VERSION 5.7 ;
BUSBITCHARS "[]" ;
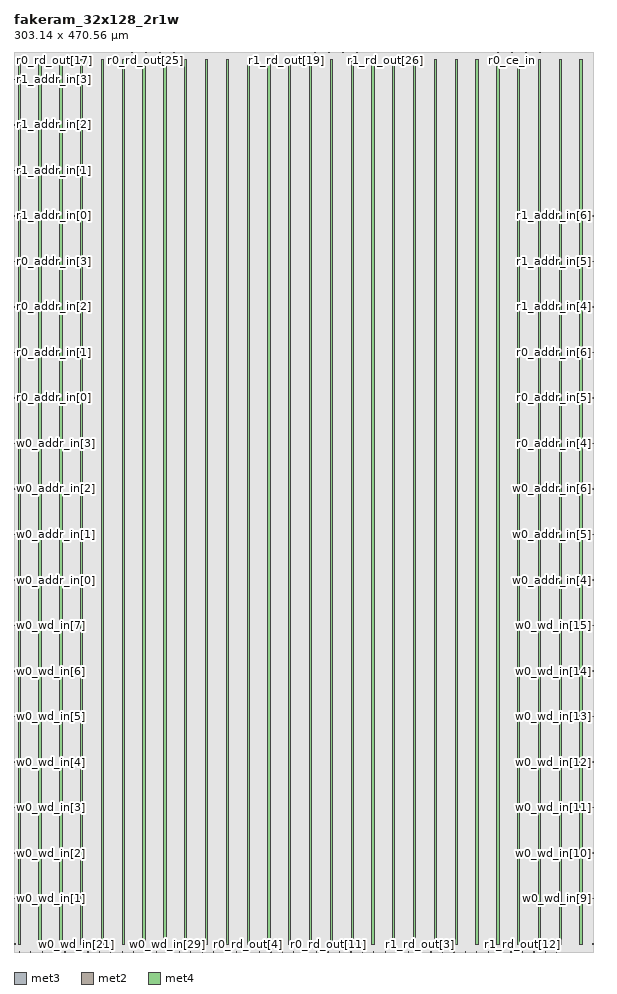
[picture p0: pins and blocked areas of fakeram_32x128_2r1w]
MACRO fakeram_32x128_2r1w
  FOREIGN fakeram_32x128_2r1w 0 0 ;
  SYMMETRY X Y R90 ;
  SIZE 303.140 BY 470.560 ;
  CLASS BLOCK ;
  PIN w0_wd_in[0]
    DIRECTION INPUT ;
    USE SIGNAL ;
    SHAPE ABUTMENT ;
    PORT
      LAYER met3 ;
      RECT 0.000 3.930 0.900 4.230 ;
    END
  END w0_wd_in[0]
  PIN w0_wd_in[1]
    DIRECTION INPUT ;
    USE SIGNAL ;
    SHAPE ABUTMENT ;
    PORT
      LAYER met3 ;
      RECT 0.000 27.730 0.900 28.030 ;
    END
  END w0_wd_in[1]
  PIN w0_wd_in[2]
    DIRECTION INPUT ;
    USE SIGNAL ;
    SHAPE ABUTMENT ;
    PORT
      LAYER met3 ;
      RECT 0.000 51.530 0.900 51.830 ;
    END
  END w0_wd_in[2]
  PIN w0_wd_in[3]
    DIRECTION INPUT ;
    USE SIGNAL ;
    SHAPE ABUTMENT ;
    PORT
      LAYER met3 ;
      RECT 0.000 75.330 0.900 75.630 ;
    END
  END w0_wd_in[3]
  PIN w0_wd_in[4]
    DIRECTION INPUT ;
    USE SIGNAL ;
    SHAPE ABUTMENT ;
    PORT
      LAYER met3 ;
      RECT 0.000 99.130 0.900 99.430 ;
    END
  END w0_wd_in[4]
  PIN w0_wd_in[5]
    DIRECTION INPUT ;
    USE SIGNAL ;
    SHAPE ABUTMENT ;
    PORT
      LAYER met3 ;
      RECT 0.000 122.930 0.900 123.230 ;
    END
  END w0_wd_in[5]
  PIN w0_wd_in[6]
    DIRECTION INPUT ;
    USE SIGNAL ;
    SHAPE ABUTMENT ;
    PORT
      LAYER met3 ;
      RECT 0.000 146.730 0.900 147.030 ;
    END
  END w0_wd_in[6]
  PIN w0_wd_in[7]
    DIRECTION INPUT ;
    USE SIGNAL ;
    SHAPE ABUTMENT ;
    PORT
      LAYER met3 ;
      RECT 0.000 170.530 0.900 170.830 ;
    END
  END w0_wd_in[7]
  PIN w0_wd_in[8]
    DIRECTION INPUT ;
    USE SIGNAL ;
    SHAPE ABUTMENT ;
    PORT
      LAYER met3 ;
      RECT 302.240 3.930 303.140 4.230 ;
    END
  END w0_wd_in[8]
  PIN w0_wd_in[9]
    DIRECTION INPUT ;
    USE SIGNAL ;
    SHAPE ABUTMENT ;
    PORT
      LAYER met3 ;
      RECT 302.240 27.730 303.140 28.030 ;
    END
  END w0_wd_in[9]
  PIN w0_wd_in[10]
    DIRECTION INPUT ;
    USE SIGNAL ;
    SHAPE ABUTMENT ;
    PORT
      LAYER met3 ;
      RECT 302.240 51.530 303.140 51.830 ;
    END
  END w0_wd_in[10]
  PIN w0_wd_in[11]
    DIRECTION INPUT ;
    USE SIGNAL ;
    SHAPE ABUTMENT ;
    PORT
      LAYER met3 ;
      RECT 302.240 75.330 303.140 75.630 ;
    END
  END w0_wd_in[11]
  PIN w0_wd_in[12]
    DIRECTION INPUT ;
    USE SIGNAL ;
    SHAPE ABUTMENT ;
    PORT
      LAYER met3 ;
      RECT 302.240 99.130 303.140 99.430 ;
    END
  END w0_wd_in[12]
  PIN w0_wd_in[13]
    DIRECTION INPUT ;
    USE SIGNAL ;
    SHAPE ABUTMENT ;
    PORT
      LAYER met3 ;
      RECT 302.240 122.930 303.140 123.230 ;
    END
  END w0_wd_in[13]
  PIN w0_wd_in[14]
    DIRECTION INPUT ;
    USE SIGNAL ;
    SHAPE ABUTMENT ;
    PORT
      LAYER met3 ;
      RECT 302.240 146.730 303.140 147.030 ;
    END
  END w0_wd_in[14]
  PIN w0_wd_in[15]
    DIRECTION INPUT ;
    USE SIGNAL ;
    SHAPE ABUTMENT ;
    PORT
      LAYER met3 ;
      RECT 302.240 170.530 303.140 170.830 ;
    END
  END w0_wd_in[15]
  PIN w0_wd_in[16]
    DIRECTION OUTPUT ;
    USE SIGNAL ;
    SHAPE ABUTMENT ;
    PORT
      LAYER met2 ;
      RECT 2.690 0.000 2.830 0.420 ;
    END
  END w0_wd_in[16]
  PIN w0_wd_in[17]
    DIRECTION OUTPUT ;
    USE SIGNAL ;
    SHAPE ABUTMENT ;
    PORT
      LAYER met2 ;
      RECT 8.670 0.000 8.810 0.420 ;
    END
  END w0_wd_in[17]
  PIN w0_wd_in[18]
    DIRECTION OUTPUT ;
    USE SIGNAL ;
    SHAPE ABUTMENT ;
    PORT
      LAYER met2 ;
      RECT 14.650 0.000 14.790 0.420 ;
    END
  END w0_wd_in[18]
  PIN w0_wd_in[19]
    DIRECTION OUTPUT ;
    USE SIGNAL ;
    SHAPE ABUTMENT ;
    PORT
      LAYER met2 ;
      RECT 20.630 0.000 20.770 0.420 ;
    END
  END w0_wd_in[19]
  PIN w0_wd_in[20]
    DIRECTION OUTPUT ;
    USE SIGNAL ;
    SHAPE ABUTMENT ;
    PORT
      LAYER met2 ;
      RECT 26.610 0.000 26.750 0.420 ;
    END
  END w0_wd_in[20]
  PIN w0_wd_in[21]
    DIRECTION OUTPUT ;
    USE SIGNAL ;
    SHAPE ABUTMENT ;
    PORT
      LAYER met2 ;
      RECT 32.590 0.000 32.730 0.420 ;
    END
  END w0_wd_in[21]
  PIN w0_wd_in[22]
    DIRECTION OUTPUT ;
    USE SIGNAL ;
    SHAPE ABUTMENT ;
    PORT
      LAYER met2 ;
      RECT 38.570 0.000 38.710 0.420 ;
    END
  END w0_wd_in[22]
  PIN w0_wd_in[23]
    DIRECTION OUTPUT ;
    USE SIGNAL ;
    SHAPE ABUTMENT ;
    PORT
      LAYER met2 ;
      RECT 44.550 0.000 44.690 0.420 ;
    END
  END w0_wd_in[23]
  PIN w0_wd_in[24]
    DIRECTION OUTPUT ;
    USE SIGNAL ;
    SHAPE ABUTMENT ;
    PORT
      LAYER met2 ;
      RECT 50.530 0.000 50.670 0.420 ;
    END
  END w0_wd_in[24]
  PIN w0_wd_in[25]
    DIRECTION OUTPUT ;
    USE SIGNAL ;
    SHAPE ABUTMENT ;
    PORT
      LAYER met2 ;
      RECT 56.510 0.000 56.650 0.420 ;
    END
  END w0_wd_in[25]
  PIN w0_wd_in[26]
    DIRECTION OUTPUT ;
    USE SIGNAL ;
    SHAPE ABUTMENT ;
    PORT
      LAYER met2 ;
      RECT 62.490 0.000 62.630 0.420 ;
    END
  END w0_wd_in[26]
  PIN w0_wd_in[27]
    DIRECTION OUTPUT ;
    USE SIGNAL ;
    SHAPE ABUTMENT ;
    PORT
      LAYER met2 ;
      RECT 68.470 0.000 68.610 0.420 ;
    END
  END w0_wd_in[27]
  PIN w0_wd_in[28]
    DIRECTION OUTPUT ;
    USE SIGNAL ;
    SHAPE ABUTMENT ;
    PORT
      LAYER met2 ;
      RECT 74.450 0.000 74.590 0.420 ;
    END
  END w0_wd_in[28]
  PIN w0_wd_in[29]
    DIRECTION OUTPUT ;
    USE SIGNAL ;
    SHAPE ABUTMENT ;
    PORT
      LAYER met2 ;
      RECT 80.430 0.000 80.570 0.420 ;
    END
  END w0_wd_in[29]
  PIN w0_wd_in[30]
    DIRECTION OUTPUT ;
    USE SIGNAL ;
    SHAPE ABUTMENT ;
    PORT
      LAYER met2 ;
      RECT 86.410 0.000 86.550 0.420 ;
    END
  END w0_wd_in[30]
  PIN w0_wd_in[31]
    DIRECTION OUTPUT ;
    USE SIGNAL ;
    SHAPE ABUTMENT ;
    PORT
      LAYER met2 ;
      RECT 92.390 0.000 92.530 0.420 ;
    END
  END w0_wd_in[31]
  PIN r0_rd_out[0]
    DIRECTION OUTPUT ;
    USE SIGNAL ;
    SHAPE ABUTMENT ;
    PORT
      LAYER met2 ;
      RECT 98.370 0.000 98.510 0.420 ;
    END
  END r0_rd_out[0]
  PIN r0_rd_out[1]
    DIRECTION OUTPUT ;
    USE SIGNAL ;
    SHAPE ABUTMENT ;
    PORT
      LAYER met2 ;
      RECT 104.350 0.000 104.490 0.420 ;
    END
  END r0_rd_out[1]
  PIN r0_rd_out[2]
    DIRECTION OUTPUT ;
    USE SIGNAL ;
    SHAPE ABUTMENT ;
    PORT
      LAYER met2 ;
      RECT 110.330 0.000 110.470 0.420 ;
    END
  END r0_rd_out[2]
  PIN r0_rd_out[3]
    DIRECTION OUTPUT ;
    USE SIGNAL ;
    SHAPE ABUTMENT ;
    PORT
      LAYER met2 ;
      RECT 116.310 0.000 116.450 0.420 ;
    END
  END r0_rd_out[3]
  PIN r0_rd_out[4]
    DIRECTION OUTPUT ;
    USE SIGNAL ;
    SHAPE ABUTMENT ;
    PORT
      LAYER met2 ;
      RECT 122.290 0.000 122.430 0.420 ;
    END
  END r0_rd_out[4]
  PIN r0_rd_out[5]
    DIRECTION OUTPUT ;
    USE SIGNAL ;
    SHAPE ABUTMENT ;
    PORT
      LAYER met2 ;
      RECT 128.270 0.000 128.410 0.420 ;
    END
  END r0_rd_out[5]
  PIN r0_rd_out[6]
    DIRECTION OUTPUT ;
    USE SIGNAL ;
    SHAPE ABUTMENT ;
    PORT
      LAYER met2 ;
      RECT 134.250 0.000 134.390 0.420 ;
    END
  END r0_rd_out[6]
  PIN r0_rd_out[7]
    DIRECTION OUTPUT ;
    USE SIGNAL ;
    SHAPE ABUTMENT ;
    PORT
      LAYER met2 ;
      RECT 140.230 0.000 140.370 0.420 ;
    END
  END r0_rd_out[7]
  PIN r0_rd_out[8]
    DIRECTION OUTPUT ;
    USE SIGNAL ;
    SHAPE ABUTMENT ;
    PORT
      LAYER met2 ;
      RECT 146.210 0.000 146.350 0.420 ;
    END
  END r0_rd_out[8]
  PIN r0_rd_out[9]
    DIRECTION OUTPUT ;
    USE SIGNAL ;
    SHAPE ABUTMENT ;
    PORT
      LAYER met2 ;
      RECT 152.190 0.000 152.330 0.420 ;
    END
  END r0_rd_out[9]
  PIN r0_rd_out[10]
    DIRECTION OUTPUT ;
    USE SIGNAL ;
    SHAPE ABUTMENT ;
    PORT
      LAYER met2 ;
      RECT 158.170 0.000 158.310 0.420 ;
    END
  END r0_rd_out[10]
  PIN r0_rd_out[11]
    DIRECTION OUTPUT ;
    USE SIGNAL ;
    SHAPE ABUTMENT ;
    PORT
      LAYER met2 ;
      RECT 164.150 0.000 164.290 0.420 ;
    END
  END r0_rd_out[11]
  PIN r0_rd_out[12]
    DIRECTION OUTPUT ;
    USE SIGNAL ;
    SHAPE ABUTMENT ;
    PORT
      LAYER met2 ;
      RECT 170.130 0.000 170.270 0.420 ;
    END
  END r0_rd_out[12]
  PIN r0_rd_out[13]
    DIRECTION OUTPUT ;
    USE SIGNAL ;
    SHAPE ABUTMENT ;
    PORT
      LAYER met2 ;
      RECT 176.110 0.000 176.250 0.420 ;
    END
  END r0_rd_out[13]
  PIN r0_rd_out[14]
    DIRECTION OUTPUT ;
    USE SIGNAL ;
    SHAPE ABUTMENT ;
    PORT
      LAYER met2 ;
      RECT 182.090 0.000 182.230 0.420 ;
    END
  END r0_rd_out[14]
  PIN r0_rd_out[15]
    DIRECTION OUTPUT ;
    USE SIGNAL ;
    SHAPE ABUTMENT ;
    PORT
      LAYER met2 ;
      RECT 188.070 0.000 188.210 0.420 ;
    END
  END r0_rd_out[15]
  PIN r0_rd_out[16]
    DIRECTION OUTPUT ;
    USE SIGNAL ;
    SHAPE ABUTMENT ;
    PORT
      LAYER met2 ;
      RECT 2.690 470.140 2.830 470.560 ;
    END
  END r0_rd_out[16]
  PIN r0_rd_out[17]
    DIRECTION OUTPUT ;
    USE SIGNAL ;
    SHAPE ABUTMENT ;
    PORT
      LAYER met2 ;
      RECT 10.050 470.140 10.190 470.560 ;
    END
  END r0_rd_out[17]
  PIN r0_rd_out[18]
    DIRECTION OUTPUT ;
    USE SIGNAL ;
    SHAPE ABUTMENT ;
    PORT
      LAYER met2 ;
      RECT 17.410 470.140 17.550 470.560 ;
    END
  END r0_rd_out[18]
  PIN r0_rd_out[19]
    DIRECTION OUTPUT ;
    USE SIGNAL ;
    SHAPE ABUTMENT ;
    PORT
      LAYER met2 ;
      RECT 24.770 470.140 24.910 470.560 ;
    END
  END r0_rd_out[19]
  PIN r0_rd_out[20]
    DIRECTION OUTPUT ;
    USE SIGNAL ;
    SHAPE ABUTMENT ;
    PORT
      LAYER met2 ;
      RECT 32.130 470.140 32.270 470.560 ;
    END
  END r0_rd_out[20]
  PIN r0_rd_out[21]
    DIRECTION OUTPUT ;
    USE SIGNAL ;
    SHAPE ABUTMENT ;
    PORT
      LAYER met2 ;
      RECT 39.490 470.140 39.630 470.560 ;
    END
  END r0_rd_out[21]
  PIN r0_rd_out[22]
    DIRECTION OUTPUT ;
    USE SIGNAL ;
    SHAPE ABUTMENT ;
    PORT
      LAYER met2 ;
      RECT 46.850 470.140 46.990 470.560 ;
    END
  END r0_rd_out[22]
  PIN r0_rd_out[23]
    DIRECTION OUTPUT ;
    USE SIGNAL ;
    SHAPE ABUTMENT ;
    PORT
      LAYER met2 ;
      RECT 54.210 470.140 54.350 470.560 ;
    END
  END r0_rd_out[23]
  PIN r0_rd_out[24]
    DIRECTION OUTPUT ;
    USE SIGNAL ;
    SHAPE ABUTMENT ;
    PORT
      LAYER met2 ;
      RECT 61.570 470.140 61.710 470.560 ;
    END
  END r0_rd_out[24]
  PIN r0_rd_out[25]
    DIRECTION OUTPUT ;
    USE SIGNAL ;
    SHAPE ABUTMENT ;
    PORT
      LAYER met2 ;
      RECT 68.930 470.140 69.070 470.560 ;
    END
  END r0_rd_out[25]
  PIN r0_rd_out[26]
    DIRECTION OUTPUT ;
    USE SIGNAL ;
    SHAPE ABUTMENT ;
    PORT
      LAYER met2 ;
      RECT 76.290 470.140 76.430 470.560 ;
    END
  END r0_rd_out[26]
  PIN r0_rd_out[27]
    DIRECTION OUTPUT ;
    USE SIGNAL ;
    SHAPE ABUTMENT ;
    PORT
      LAYER met2 ;
      RECT 83.650 470.140 83.790 470.560 ;
    END
  END r0_rd_out[27]
  PIN r0_rd_out[28]
    DIRECTION OUTPUT ;
    USE SIGNAL ;
    SHAPE ABUTMENT ;
    PORT
      LAYER met2 ;
      RECT 91.010 470.140 91.150 470.560 ;
    END
  END r0_rd_out[28]
  PIN r0_rd_out[29]
    DIRECTION OUTPUT ;
    USE SIGNAL ;
    SHAPE ABUTMENT ;
    PORT
      LAYER met2 ;
      RECT 98.370 470.140 98.510 470.560 ;
    END
  END r0_rd_out[29]
  PIN r0_rd_out[30]
    DIRECTION OUTPUT ;
    USE SIGNAL ;
    SHAPE ABUTMENT ;
    PORT
      LAYER met2 ;
      RECT 105.730 470.140 105.870 470.560 ;
    END
  END r0_rd_out[30]
  PIN r0_rd_out[31]
    DIRECTION OUTPUT ;
    USE SIGNAL ;
    SHAPE ABUTMENT ;
    PORT
      LAYER met2 ;
      RECT 113.090 470.140 113.230 470.560 ;
    END
  END r0_rd_out[31]
  PIN r1_rd_out[0]
    DIRECTION OUTPUT ;
    USE SIGNAL ;
    SHAPE ABUTMENT ;
    PORT
      LAYER met2 ;
      RECT 194.050 0.000 194.190 0.420 ;
    END
  END r1_rd_out[0]
  PIN r1_rd_out[1]
    DIRECTION OUTPUT ;
    USE SIGNAL ;
    SHAPE ABUTMENT ;
    PORT
      LAYER met2 ;
      RECT 200.030 0.000 200.170 0.420 ;
    END
  END r1_rd_out[1]
  PIN r1_rd_out[2]
    DIRECTION OUTPUT ;
    USE SIGNAL ;
    SHAPE ABUTMENT ;
    PORT
      LAYER met2 ;
      RECT 206.010 0.000 206.150 0.420 ;
    END
  END r1_rd_out[2]
  PIN r1_rd_out[3]
    DIRECTION OUTPUT ;
    USE SIGNAL ;
    SHAPE ABUTMENT ;
    PORT
      LAYER met2 ;
      RECT 211.990 0.000 212.130 0.420 ;
    END
  END r1_rd_out[3]
  PIN r1_rd_out[4]
    DIRECTION OUTPUT ;
    USE SIGNAL ;
    SHAPE ABUTMENT ;
    PORT
      LAYER met2 ;
      RECT 217.970 0.000 218.110 0.420 ;
    END
  END r1_rd_out[4]
  PIN r1_rd_out[5]
    DIRECTION OUTPUT ;
    USE SIGNAL ;
    SHAPE ABUTMENT ;
    PORT
      LAYER met2 ;
      RECT 223.950 0.000 224.090 0.420 ;
    END
  END r1_rd_out[5]
  PIN r1_rd_out[6]
    DIRECTION OUTPUT ;
    USE SIGNAL ;
    SHAPE ABUTMENT ;
    PORT
      LAYER met2 ;
      RECT 229.930 0.000 230.070 0.420 ;
    END
  END r1_rd_out[6]
  PIN r1_rd_out[7]
    DIRECTION OUTPUT ;
    USE SIGNAL ;
    SHAPE ABUTMENT ;
    PORT
      LAYER met2 ;
      RECT 235.910 0.000 236.050 0.420 ;
    END
  END r1_rd_out[7]
  PIN r1_rd_out[8]
    DIRECTION OUTPUT ;
    USE SIGNAL ;
    SHAPE ABUTMENT ;
    PORT
      LAYER met2 ;
      RECT 241.890 0.000 242.030 0.420 ;
    END
  END r1_rd_out[8]
  PIN r1_rd_out[9]
    DIRECTION OUTPUT ;
    USE SIGNAL ;
    SHAPE ABUTMENT ;
    PORT
      LAYER met2 ;
      RECT 247.870 0.000 248.010 0.420 ;
    END
  END r1_rd_out[9]
  PIN r1_rd_out[10]
    DIRECTION OUTPUT ;
    USE SIGNAL ;
    SHAPE ABUTMENT ;
    PORT
      LAYER met2 ;
      RECT 253.850 0.000 253.990 0.420 ;
    END
  END r1_rd_out[10]
  PIN r1_rd_out[11]
    DIRECTION OUTPUT ;
    USE SIGNAL ;
    SHAPE ABUTMENT ;
    PORT
      LAYER met2 ;
      RECT 259.830 0.000 259.970 0.420 ;
    END
  END r1_rd_out[11]
  PIN r1_rd_out[12]
    DIRECTION OUTPUT ;
    USE SIGNAL ;
    SHAPE ABUTMENT ;
    PORT
      LAYER met2 ;
      RECT 265.810 0.000 265.950 0.420 ;
    END
  END r1_rd_out[12]
  PIN r1_rd_out[13]
    DIRECTION OUTPUT ;
    USE SIGNAL ;
    SHAPE ABUTMENT ;
    PORT
      LAYER met2 ;
      RECT 271.790 0.000 271.930 0.420 ;
    END
  END r1_rd_out[13]
  PIN r1_rd_out[14]
    DIRECTION OUTPUT ;
    USE SIGNAL ;
    SHAPE ABUTMENT ;
    PORT
      LAYER met2 ;
      RECT 277.770 0.000 277.910 0.420 ;
    END
  END r1_rd_out[14]
  PIN r1_rd_out[15]
    DIRECTION OUTPUT ;
    USE SIGNAL ;
    SHAPE ABUTMENT ;
    PORT
      LAYER met2 ;
      RECT 283.750 0.000 283.890 0.420 ;
    END
  END r1_rd_out[15]
  PIN r1_rd_out[16]
    DIRECTION OUTPUT ;
    USE SIGNAL ;
    SHAPE ABUTMENT ;
    PORT
      LAYER met2 ;
      RECT 120.450 470.140 120.590 470.560 ;
    END
  END r1_rd_out[16]
  PIN r1_rd_out[17]
    DIRECTION OUTPUT ;
    USE SIGNAL ;
    SHAPE ABUTMENT ;
    PORT
      LAYER met2 ;
      RECT 127.810 470.140 127.950 470.560 ;
    END
  END r1_rd_out[17]
  PIN r1_rd_out[18]
    DIRECTION OUTPUT ;
    USE SIGNAL ;
    SHAPE ABUTMENT ;
    PORT
      LAYER met2 ;
      RECT 135.170 470.140 135.310 470.560 ;
    END
  END r1_rd_out[18]
  PIN r1_rd_out[19]
    DIRECTION OUTPUT ;
    USE SIGNAL ;
    SHAPE ABUTMENT ;
    PORT
      LAYER met2 ;
      RECT 142.530 470.140 142.670 470.560 ;
    END
  END r1_rd_out[19]
  PIN r1_rd_out[20]
    DIRECTION OUTPUT ;
    USE SIGNAL ;
    SHAPE ABUTMENT ;
    PORT
      LAYER met2 ;
      RECT 149.890 470.140 150.030 470.560 ;
    END
  END r1_rd_out[20]
  PIN r1_rd_out[21]
    DIRECTION OUTPUT ;
    USE SIGNAL ;
    SHAPE ABUTMENT ;
    PORT
      LAYER met2 ;
      RECT 157.250 470.140 157.390 470.560 ;
    END
  END r1_rd_out[21]
  PIN r1_rd_out[22]
    DIRECTION OUTPUT ;
    USE SIGNAL ;
    SHAPE ABUTMENT ;
    PORT
      LAYER met2 ;
      RECT 164.610 470.140 164.750 470.560 ;
    END
  END r1_rd_out[22]
  PIN r1_rd_out[23]
    DIRECTION OUTPUT ;
    USE SIGNAL ;
    SHAPE ABUTMENT ;
    PORT
      LAYER met2 ;
      RECT 171.970 470.140 172.110 470.560 ;
    END
  END r1_rd_out[23]
  PIN r1_rd_out[24]
    DIRECTION OUTPUT ;
    USE SIGNAL ;
    SHAPE ABUTMENT ;
    PORT
      LAYER met2 ;
      RECT 179.330 470.140 179.470 470.560 ;
    END
  END r1_rd_out[24]
  PIN r1_rd_out[25]
    DIRECTION OUTPUT ;
    USE SIGNAL ;
    SHAPE ABUTMENT ;
    PORT
      LAYER met2 ;
      RECT 186.690 470.140 186.830 470.560 ;
    END
  END r1_rd_out[25]
  PIN r1_rd_out[26]
    DIRECTION OUTPUT ;
    USE SIGNAL ;
    SHAPE ABUTMENT ;
    PORT
      LAYER met2 ;
      RECT 194.050 470.140 194.190 470.560 ;
    END
  END r1_rd_out[26]
  PIN r1_rd_out[27]
    DIRECTION OUTPUT ;
    USE SIGNAL ;
    SHAPE ABUTMENT ;
    PORT
      LAYER met2 ;
      RECT 201.410 470.140 201.550 470.560 ;
    END
  END r1_rd_out[27]
  PIN r1_rd_out[28]
    DIRECTION OUTPUT ;
    USE SIGNAL ;
    SHAPE ABUTMENT ;
    PORT
      LAYER met2 ;
      RECT 208.770 470.140 208.910 470.560 ;
    END
  END r1_rd_out[28]
  PIN r1_rd_out[29]
    DIRECTION OUTPUT ;
    USE SIGNAL ;
    SHAPE ABUTMENT ;
    PORT
      LAYER met2 ;
      RECT 216.130 470.140 216.270 470.560 ;
    END
  END r1_rd_out[29]
  PIN r1_rd_out[30]
    DIRECTION OUTPUT ;
    USE SIGNAL ;
    SHAPE ABUTMENT ;
    PORT
      LAYER met2 ;
      RECT 223.490 470.140 223.630 470.560 ;
    END
  END r1_rd_out[30]
  PIN r1_rd_out[31]
    DIRECTION OUTPUT ;
    USE SIGNAL ;
    SHAPE ABUTMENT ;
    PORT
      LAYER met2 ;
      RECT 230.850 470.140 230.990 470.560 ;
    END
  END r1_rd_out[31]
  PIN w0_addr_in[0]
    DIRECTION INPUT ;
    USE SIGNAL ;
    SHAPE ABUTMENT ;
    PORT
      LAYER met3 ;
      RECT 0.000 194.330 0.900 194.630 ;
    END
  END w0_addr_in[0]
  PIN w0_addr_in[1]
    DIRECTION INPUT ;
    USE SIGNAL ;
    SHAPE ABUTMENT ;
    PORT
      LAYER met3 ;
      RECT 0.000 218.130 0.900 218.430 ;
    END
  END w0_addr_in[1]
  PIN w0_addr_in[2]
    DIRECTION INPUT ;
    USE SIGNAL ;
    SHAPE ABUTMENT ;
    PORT
      LAYER met3 ;
      RECT 0.000 241.930 0.900 242.230 ;
    END
  END w0_addr_in[2]
  PIN w0_addr_in[3]
    DIRECTION INPUT ;
    USE SIGNAL ;
    SHAPE ABUTMENT ;
    PORT
      LAYER met3 ;
      RECT 0.000 265.730 0.900 266.030 ;
    END
  END w0_addr_in[3]
  PIN w0_addr_in[4]
    DIRECTION INPUT ;
    USE SIGNAL ;
    SHAPE ABUTMENT ;
    PORT
      LAYER met3 ;
      RECT 302.240 194.330 303.140 194.630 ;
    END
  END w0_addr_in[4]
  PIN w0_addr_in[5]
    DIRECTION INPUT ;
    USE SIGNAL ;
    SHAPE ABUTMENT ;
    PORT
      LAYER met3 ;
      RECT 302.240 218.130 303.140 218.430 ;
    END
  END w0_addr_in[5]
  PIN w0_addr_in[6]
    DIRECTION INPUT ;
    USE SIGNAL ;
    SHAPE ABUTMENT ;
    PORT
      LAYER met3 ;
      RECT 302.240 241.930 303.140 242.230 ;
    END
  END w0_addr_in[6]
  PIN r0_addr_in[0]
    DIRECTION INPUT ;
    USE SIGNAL ;
    SHAPE ABUTMENT ;
    PORT
      LAYER met3 ;
      RECT 0.000 289.530 0.900 289.830 ;
    END
  END r0_addr_in[0]
  PIN r0_addr_in[1]
    DIRECTION INPUT ;
    USE SIGNAL ;
    SHAPE ABUTMENT ;
    PORT
      LAYER met3 ;
      RECT 0.000 313.330 0.900 313.630 ;
    END
  END r0_addr_in[1]
  PIN r0_addr_in[2]
    DIRECTION INPUT ;
    USE SIGNAL ;
    SHAPE ABUTMENT ;
    PORT
      LAYER met3 ;
      RECT 0.000 337.130 0.900 337.430 ;
    END
  END r0_addr_in[2]
  PIN r0_addr_in[3]
    DIRECTION INPUT ;
    USE SIGNAL ;
    SHAPE ABUTMENT ;
    PORT
      LAYER met3 ;
      RECT 0.000 360.930 0.900 361.230 ;
    END
  END r0_addr_in[3]
  PIN r0_addr_in[4]
    DIRECTION INPUT ;
    USE SIGNAL ;
    SHAPE ABUTMENT ;
    PORT
      LAYER met3 ;
      RECT 302.240 265.730 303.140 266.030 ;
    END
  END r0_addr_in[4]
  PIN r0_addr_in[5]
    DIRECTION INPUT ;
    USE SIGNAL ;
    SHAPE ABUTMENT ;
    PORT
      LAYER met3 ;
      RECT 302.240 289.530 303.140 289.830 ;
    END
  END r0_addr_in[5]
  PIN r0_addr_in[6]
    DIRECTION INPUT ;
    USE SIGNAL ;
    SHAPE ABUTMENT ;
    PORT
      LAYER met3 ;
      RECT 302.240 313.330 303.140 313.630 ;
    END
  END r0_addr_in[6]
  PIN r1_addr_in[0]
    DIRECTION INPUT ;
    USE SIGNAL ;
    SHAPE ABUTMENT ;
    PORT
      LAYER met3 ;
      RECT 0.000 384.730 0.900 385.030 ;
    END
  END r1_addr_in[0]
  PIN r1_addr_in[1]
    DIRECTION INPUT ;
    USE SIGNAL ;
    SHAPE ABUTMENT ;
    PORT
      LAYER met3 ;
      RECT 0.000 408.530 0.900 408.830 ;
    END
  END r1_addr_in[1]
  PIN r1_addr_in[2]
    DIRECTION INPUT ;
    USE SIGNAL ;
    SHAPE ABUTMENT ;
    PORT
      LAYER met3 ;
      RECT 0.000 432.330 0.900 432.630 ;
    END
  END r1_addr_in[2]
  PIN r1_addr_in[3]
    DIRECTION INPUT ;
    USE SIGNAL ;
    SHAPE ABUTMENT ;
    PORT
      LAYER met3 ;
      RECT 0.000 456.130 0.900 456.430 ;
    END
  END r1_addr_in[3]
  PIN r1_addr_in[4]
    DIRECTION INPUT ;
    USE SIGNAL ;
    SHAPE ABUTMENT ;
    PORT
      LAYER met3 ;
      RECT 302.240 337.130 303.140 337.430 ;
    END
  END r1_addr_in[4]
  PIN r1_addr_in[5]
    DIRECTION INPUT ;
    USE SIGNAL ;
    SHAPE ABUTMENT ;
    PORT
      LAYER met3 ;
      RECT 302.240 360.930 303.140 361.230 ;
    END
  END r1_addr_in[5]
  PIN r1_addr_in[6]
    DIRECTION INPUT ;
    USE SIGNAL ;
    SHAPE ABUTMENT ;
    PORT
      LAYER met3 ;
      RECT 302.240 384.730 303.140 385.030 ;
    END
  END r1_addr_in[6]
  PIN w0_we_in
    DIRECTION INPUT ;
    USE SIGNAL ;
    SHAPE ABUTMENT ;
    PORT
      LAYER met2 ;
      RECT 238.210 470.140 238.350 470.560 ;
    END
  END w0_we_in
  PIN w0_ce_in
    DIRECTION INPUT ;
    USE SIGNAL ;
    SHAPE ABUTMENT ;
    PORT
      LAYER met2 ;
      RECT 245.570 470.140 245.710 470.560 ;
    END
  END w0_ce_in
  PIN w0_clk
    DIRECTION INPUT ;
    USE SIGNAL ;
    SHAPE ABUTMENT ;
    PORT
      LAYER met2 ;
      RECT 252.930 470.140 253.070 470.560 ;
    END
  END w0_clk
  PIN r0_ce_in
    DIRECTION INPUT ;
    USE SIGNAL ;
    SHAPE ABUTMENT ;
    PORT
      LAYER met2 ;
      RECT 260.290 470.140 260.430 470.560 ;
    END
  END r0_ce_in
  PIN r0_clk
    DIRECTION INPUT ;
    USE SIGNAL ;
    SHAPE ABUTMENT ;
    PORT
      LAYER met2 ;
      RECT 267.650 470.140 267.790 470.560 ;
    END
  END r0_clk
  PIN r1_ce_in
    DIRECTION INPUT ;
    USE SIGNAL ;
    SHAPE ABUTMENT ;
    PORT
      LAYER met2 ;
      RECT 275.010 470.140 275.150 470.560 ;
    END
  END r1_ce_in
  PIN r1_clk
    DIRECTION INPUT ;
    USE SIGNAL ;
    SHAPE ABUTMENT ;
    PORT
      LAYER met2 ;
      RECT 282.370 470.140 282.510 470.560 ;
    END
  END r1_clk
  PIN VSS
    DIRECTION INOUT ;
    USE GROUND ;
    PORT
      LAYER met4 ;
      RECT 2.160 4.080 3.360 466.480 ;
      RECT 13.040 4.080 14.240 466.480 ;
      RECT 23.920 4.080 25.120 466.480 ;
      RECT 34.800 4.080 36.000 466.480 ;
      RECT 45.680 4.080 46.880 466.480 ;
      RECT 56.560 4.080 57.760 466.480 ;
      RECT 67.440 4.080 68.640 466.480 ;
      RECT 78.320 4.080 79.520 466.480 ;
      RECT 89.200 4.080 90.400 466.480 ;
      RECT 100.080 4.080 101.280 466.480 ;
      RECT 110.960 4.080 112.160 466.480 ;
      RECT 121.840 4.080 123.040 466.480 ;
      RECT 132.720 4.080 133.920 466.480 ;
      RECT 143.600 4.080 144.800 466.480 ;
      RECT 154.480 4.080 155.680 466.480 ;
      RECT 165.360 4.080 166.560 466.480 ;
      RECT 176.240 4.080 177.440 466.480 ;
      RECT 187.120 4.080 188.320 466.480 ;
      RECT 198.000 4.080 199.200 466.480 ;
      RECT 208.880 4.080 210.080 466.480 ;
      RECT 219.760 4.080 220.960 466.480 ;
      RECT 230.640 4.080 231.840 466.480 ;
      RECT 241.520 4.080 242.720 466.480 ;
      RECT 252.400 4.080 253.600 466.480 ;
      RECT 263.280 4.080 264.480 466.480 ;
      RECT 274.160 4.080 275.360 466.480 ;
      RECT 285.040 4.080 286.240 466.480 ;
      RECT 295.920 4.080 297.120 466.480 ;
    END
  END VSS
  PIN VDD
    DIRECTION INOUT ;
    USE POWER ;
    PORT
      LAYER met4 ;
      RECT 2.160 4.080 3.360 466.480 ;
      RECT 13.040 4.080 14.240 466.480 ;
      RECT 23.920 4.080 25.120 466.480 ;
      RECT 34.800 4.080 36.000 466.480 ;
      RECT 45.680 4.080 46.880 466.480 ;
      RECT 56.560 4.080 57.760 466.480 ;
      RECT 67.440 4.080 68.640 466.480 ;
      RECT 78.320 4.080 79.520 466.480 ;
      RECT 89.200 4.080 90.400 466.480 ;
      RECT 100.080 4.080 101.280 466.480 ;
      RECT 110.960 4.080 112.160 466.480 ;
      RECT 121.840 4.080 123.040 466.480 ;
      RECT 132.720 4.080 133.920 466.480 ;
      RECT 143.600 4.080 144.800 466.480 ;
      RECT 154.480 4.080 155.680 466.480 ;
      RECT 165.360 4.080 166.560 466.480 ;
      RECT 176.240 4.080 177.440 466.480 ;
      RECT 187.120 4.080 188.320 466.480 ;
      RECT 198.000 4.080 199.200 466.480 ;
      RECT 208.880 4.080 210.080 466.480 ;
      RECT 219.760 4.080 220.960 466.480 ;
      RECT 230.640 4.080 231.840 466.480 ;
      RECT 241.520 4.080 242.720 466.480 ;
      RECT 252.400 4.080 253.600 466.480 ;
      RECT 263.280 4.080 264.480 466.480 ;
      RECT 274.160 4.080 275.360 466.480 ;
      RECT 285.040 4.080 286.240 466.480 ;
      RECT 295.920 4.080 297.120 466.480 ;
    END
  END VDD
  OBS
    LAYER met1 ;
    RECT 0 0 303.140 470.560 ;
    LAYER met2 ;
    RECT 0 0 303.140 470.560 ;
    LAYER met3 ;
    RECT 0 0 303.140 470.560 ;
    LAYER met4 ;
    RECT 0 0 303.140 470.560 ;
  END
END fakeram_32x128_2r1w

END LIBRARY
